########################################################################
#
# Copyright 2025 IHP PDK Authors
#
# Licensed under the Apache License, Version 2.0 (the "License");
# you may not use this file except in compliance with the License.
# You may obtain a copy of the License at
#
#    https://www.apache.org/licenses/LICENSE-2.0
#
# Unless required by applicable law or agreed to in writing, software
# distributed under the License is distributed on an "AS IS" BASIS,
# WITHOUT WARRANTIES OR CONDITIONS OF ANY KIND, either express or implied.
# See the License for the specific language governing permissions and
# limitations under the License.
#
########################################################################

VERSION 5.7 ;
BUSBITCHARS "<>" ;
DIVIDERCHAR "/" ;

PROPERTYDEFINITIONS
  MACRO CatenaDesignType STRING ;
END PROPERTYDEFINITIONS

SITE  CoreSite
    CLASS       CORE ;
    SYMMETRY    Y ;
    SIZE        0.48 BY 3.78 ;
END  CoreSite

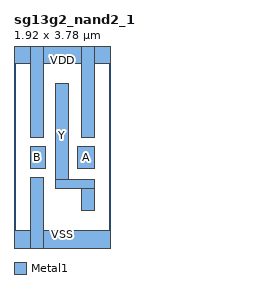
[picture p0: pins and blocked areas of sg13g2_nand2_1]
MACRO sg13g2_nand2_1
  CLASS CORE ;
  ORIGIN 0 0 ;
  FOREIGN sg13g2_nand2_1 0 0 ;
  SIZE 1.92 BY 3.78 ;
  SYMMETRY X Y ;
  SITE CoreSite ;
  PIN Y
    DIRECTION OUTPUT ;
    USE SIGNAL ;
    ANTENNADIFFAREA 0.6772 LAYER Metal1 ;
    PORT
      LAYER Metal1 ;
        RECT 0.83 1.06 1.6 1.245 ;
        RECT 1.34 0.62 1.6 1.245 ;
        RECT 0.83 1.06 1.09 3.16 ;
    END
  END Y
  PIN A
    DIRECTION INPUT ;
    USE SIGNAL ;
    ANTENNAMODEL OXIDE1 ;
      ANTENNAGATEAREA 0.2418 LAYER Metal1 ;
    PORT
      LAYER Metal1 ;
        RECT 1.27 1.47 1.6 1.9 ;
    END
  END A
  PIN B
    DIRECTION INPUT ;
    USE SIGNAL ;
    ANTENNAMODEL OXIDE1 ;
      ANTENNAGATEAREA 0.2418 LAYER Metal1 ;
    PORT
      LAYER Metal1 ;
        RECT 0.33 1.47 0.62 1.9 ;
    END
  END B
  PIN VDD
    DIRECTION INOUT ;
    USE POWER ;
    SHAPE ABUTMENT ;
    NETEXPR "VDD VDD!" ;
    PORT
      LAYER Metal1 ;
        RECT 0 3.56 1.92 4 ;
        RECT 1.34 2.08 1.6 4 ;
        RECT 0.32 2.08 0.58 4 ;
    END
  END VDD
  PIN VSS
    DIRECTION INOUT ;
    USE GROUND ;
    SHAPE ABUTMENT ;
    NETEXPR "VSS VSS!" ;
    PORT
      LAYER Metal1 ;
        RECT 0 -0.22 1.92 0.22 ;
        RECT 0.32 -0.22 0.58 1.275 ;
    END
  END VSS
  PROPERTY CatenaDesignType "deviceLevel" ;
END sg13g2_nand2_1
END LIBRARY
